VERSION 5.7 ;
  DIVIDERCHAR "/" ;
  BUSBITCHARS "[]" ;
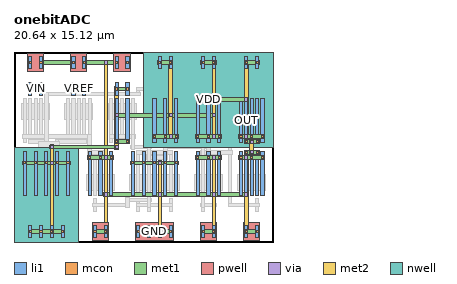
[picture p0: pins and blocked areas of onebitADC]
MACRO onebitADC
  CLASS BLOCK ;
  FOREIGN onebitADC ;
  ORIGIN 0.000 0.000 ;
  SIZE 20.640 BY 15.120 ;
  PIN VIN
    ANTENNAGATEAREA 0.630000 ;
    PORT
      LAYER li1 ;
        RECT 1.165 11.675 1.415 12.685 ;
        RECT 2.025 11.675 2.275 12.685 ;
      LAYER mcon ;
        RECT 1.205 12.095 1.375 12.265 ;
        RECT 2.065 12.095 2.235 12.265 ;
      LAYER met1 ;
        RECT 1.120 12.040 2.320 12.320 ;
    END
  END VIN
  PIN GND
    ANTENNADIFFAREA 7.036400 ;
    PORT
      LAYER pwell ;
        RECT 1.075 13.590 2.365 14.970 ;
        RECT 4.515 13.590 5.805 14.970 ;
        RECT 7.955 13.590 9.245 14.970 ;
        RECT 6.235 0.150 7.525 1.530 ;
        RECT 9.675 0.150 12.685 1.530 ;
        RECT 14.835 0.150 16.125 1.530 ;
        RECT 18.275 0.150 19.565 1.530 ;
      LAYER li1 ;
        RECT 1.165 13.775 1.415 14.785 ;
        RECT 2.025 13.775 2.275 14.785 ;
        RECT 4.605 13.775 4.855 14.785 ;
        RECT 5.465 13.775 5.715 14.785 ;
        RECT 8.045 13.775 8.295 14.785 ;
        RECT 8.905 13.775 9.155 14.785 ;
        RECT 5.895 3.695 6.145 7.225 ;
        RECT 6.755 3.695 7.005 7.225 ;
        RECT 7.615 3.695 7.865 7.225 ;
        RECT 9.335 3.695 9.585 7.225 ;
        RECT 10.195 3.695 10.445 7.225 ;
        RECT 11.055 3.695 11.305 7.225 ;
        RECT 11.915 3.695 12.165 7.225 ;
        RECT 12.775 3.695 13.025 7.225 ;
        RECT 14.495 3.695 14.745 7.225 ;
        RECT 15.355 3.695 15.605 7.225 ;
        RECT 16.215 3.695 16.465 7.225 ;
        RECT 17.935 3.695 18.185 7.225 ;
        RECT 18.795 3.695 19.045 7.225 ;
        RECT 19.655 3.695 19.905 7.225 ;
        RECT 6.325 0.335 6.575 1.345 ;
        RECT 7.185 0.335 7.435 1.345 ;
        RECT 9.765 0.335 10.015 1.345 ;
        RECT 10.625 0.335 10.875 1.345 ;
        RECT 11.485 0.335 11.735 1.345 ;
        RECT 12.345 0.335 12.595 1.345 ;
        RECT 14.925 0.335 15.175 1.345 ;
        RECT 15.785 0.335 16.035 1.345 ;
        RECT 18.365 0.335 18.615 1.345 ;
        RECT 19.225 0.335 19.475 1.345 ;
      LAYER mcon ;
        RECT 1.205 14.195 1.375 14.365 ;
        RECT 2.065 14.195 2.235 14.365 ;
        RECT 4.645 14.195 4.815 14.365 ;
        RECT 5.505 14.195 5.675 14.365 ;
        RECT 8.085 14.195 8.255 14.365 ;
        RECT 8.945 14.195 9.115 14.365 ;
        RECT 5.935 6.635 6.105 6.805 ;
        RECT 6.795 6.635 6.965 6.805 ;
        RECT 7.655 6.635 7.825 6.805 ;
        RECT 9.375 6.215 9.545 6.385 ;
        RECT 10.235 6.215 10.405 6.385 ;
        RECT 11.095 6.215 11.265 6.385 ;
        RECT 11.955 6.215 12.125 6.385 ;
        RECT 12.815 6.215 12.985 6.385 ;
        RECT 14.535 6.635 14.705 6.805 ;
        RECT 15.395 6.635 15.565 6.805 ;
        RECT 16.255 6.635 16.425 6.805 ;
        RECT 17.975 6.635 18.145 6.805 ;
        RECT 18.835 6.635 19.005 6.805 ;
        RECT 19.695 6.635 19.865 6.805 ;
        RECT 6.365 0.755 6.535 0.925 ;
        RECT 7.225 0.755 7.395 0.925 ;
        RECT 9.805 0.755 9.975 0.925 ;
        RECT 10.665 0.755 10.835 0.925 ;
        RECT 11.525 0.755 11.695 0.925 ;
        RECT 12.385 0.755 12.555 0.925 ;
        RECT 14.965 0.755 15.135 0.925 ;
        RECT 15.825 0.755 15.995 0.925 ;
        RECT 18.405 0.755 18.575 0.925 ;
        RECT 19.265 0.755 19.435 0.925 ;
      LAYER met1 ;
        RECT 1.120 14.140 9.200 14.420 ;
        RECT 5.850 6.580 7.910 6.860 ;
        RECT 14.450 6.580 16.510 6.860 ;
        RECT 17.890 6.580 19.950 6.860 ;
        RECT 9.290 6.160 13.070 6.440 ;
        RECT 7.150 3.640 18.650 3.920 ;
        RECT 6.280 0.700 7.480 0.980 ;
        RECT 9.720 0.700 12.640 0.980 ;
        RECT 14.880 0.700 16.080 0.980 ;
        RECT 18.320 0.700 19.520 0.980 ;
      LAYER via ;
        RECT 7.180 14.150 7.440 14.410 ;
        RECT 7.180 6.590 7.440 6.850 ;
        RECT 15.780 6.590 16.040 6.850 ;
        RECT 18.360 6.590 18.620 6.850 ;
        RECT 11.480 6.170 11.740 6.430 ;
        RECT 7.180 3.650 7.440 3.910 ;
        RECT 11.480 3.650 11.740 3.910 ;
        RECT 15.780 3.650 16.040 3.910 ;
        RECT 18.360 3.650 18.620 3.910 ;
        RECT 7.180 0.710 7.440 0.970 ;
        RECT 11.480 0.710 11.740 0.970 ;
        RECT 15.780 0.710 16.040 0.970 ;
        RECT 18.360 0.710 18.620 0.970 ;
      LAYER met2 ;
        RECT 7.170 0.680 7.450 14.440 ;
        RECT 11.470 0.680 11.750 6.460 ;
        RECT 15.770 0.680 16.050 6.880 ;
        RECT 18.350 0.680 18.630 6.880 ;
    END
  END GND
  PIN OUT
    ANTENNADIFFAREA 1.176000 ;
    PORT
      LAYER li1 ;
        RECT 18.365 7.895 18.615 11.425 ;
        RECT 19.225 7.895 19.475 11.425 ;
        RECT 18.365 3.695 18.615 7.225 ;
        RECT 19.225 3.695 19.475 7.225 ;
      LAYER mcon ;
        RECT 18.405 7.895 18.575 8.065 ;
        RECT 19.265 7.895 19.435 8.065 ;
        RECT 18.405 7.055 18.575 7.225 ;
        RECT 19.265 7.055 19.435 7.225 ;
      LAYER met1 ;
        RECT 18.320 7.840 19.520 8.120 ;
        RECT 18.320 7.000 19.520 7.280 ;
      LAYER via ;
        RECT 18.790 7.850 19.050 8.110 ;
        RECT 18.790 7.010 19.050 7.270 ;
      LAYER met2 ;
        RECT 18.780 6.980 19.060 8.140 ;
    END
  END OUT
  PIN VDD
    ANTENNAGATEAREA 0.630000 ;
    ANTENNADIFFAREA 6.482000 ;
    PORT
      LAYER nwell ;
        RECT 10.320 7.560 20.640 15.120 ;
        RECT 0.000 0.000 5.160 7.560 ;
      LAYER li1 ;
        RECT 11.485 13.775 11.735 14.785 ;
        RECT 12.345 13.775 12.595 14.785 ;
        RECT 14.925 13.775 15.175 14.785 ;
        RECT 15.785 13.775 16.035 14.785 ;
        RECT 18.365 13.775 18.615 14.785 ;
        RECT 19.225 13.775 19.475 14.785 ;
        RECT 8.045 11.675 8.295 12.685 ;
        RECT 8.905 11.675 9.155 12.685 ;
        RECT 8.045 7.895 8.295 11.425 ;
        RECT 8.905 7.895 9.155 11.425 ;
        RECT 11.055 7.895 11.305 11.425 ;
        RECT 11.915 7.895 12.165 11.425 ;
        RECT 12.775 7.895 13.025 11.425 ;
        RECT 14.495 7.895 14.745 11.425 ;
        RECT 15.355 7.895 15.605 11.425 ;
        RECT 16.215 7.895 16.465 11.425 ;
        RECT 17.935 7.895 18.185 11.425 ;
        RECT 18.795 7.895 19.045 11.425 ;
        RECT 19.655 7.895 19.905 11.425 ;
        RECT 0.735 3.695 0.985 7.225 ;
        RECT 1.595 3.695 1.845 7.225 ;
        RECT 2.455 3.695 2.705 7.225 ;
        RECT 3.315 3.695 3.565 7.225 ;
        RECT 4.175 3.695 4.425 7.225 ;
        RECT 1.165 0.335 1.415 1.345 ;
        RECT 2.025 0.335 2.275 1.345 ;
        RECT 2.885 0.335 3.135 1.345 ;
        RECT 3.745 0.335 3.995 1.345 ;
      LAYER mcon ;
        RECT 11.525 14.195 11.695 14.365 ;
        RECT 12.385 14.195 12.555 14.365 ;
        RECT 14.965 14.195 15.135 14.365 ;
        RECT 15.825 14.195 15.995 14.365 ;
        RECT 18.405 14.195 18.575 14.365 ;
        RECT 19.265 14.195 19.435 14.365 ;
        RECT 8.085 12.095 8.255 12.265 ;
        RECT 8.945 12.095 9.115 12.265 ;
        RECT 8.085 7.895 8.255 8.065 ;
        RECT 8.945 7.895 9.115 8.065 ;
        RECT 11.095 8.315 11.265 8.485 ;
        RECT 11.955 8.315 12.125 8.485 ;
        RECT 12.815 8.315 12.985 8.485 ;
        RECT 14.535 8.315 14.705 8.485 ;
        RECT 15.395 8.315 15.565 8.485 ;
        RECT 16.255 8.315 16.425 8.485 ;
        RECT 17.975 8.315 18.145 8.485 ;
        RECT 18.835 8.315 19.005 8.485 ;
        RECT 19.695 8.315 19.865 8.485 ;
        RECT 0.775 6.215 0.945 6.385 ;
        RECT 1.635 6.215 1.805 6.385 ;
        RECT 2.495 6.215 2.665 6.385 ;
        RECT 3.355 6.215 3.525 6.385 ;
        RECT 4.215 6.215 4.385 6.385 ;
        RECT 1.205 0.755 1.375 0.925 ;
        RECT 2.065 0.755 2.235 0.925 ;
        RECT 2.925 0.755 3.095 0.925 ;
        RECT 3.785 0.755 3.955 0.925 ;
      LAYER met1 ;
        RECT 11.440 14.140 12.640 14.420 ;
        RECT 14.880 14.140 16.080 14.420 ;
        RECT 18.320 14.140 19.520 14.420 ;
        RECT 8.000 12.040 9.200 12.320 ;
        RECT 15.750 11.200 18.650 11.480 ;
        RECT 8.010 9.940 16.070 10.220 ;
        RECT 11.010 8.260 13.070 8.540 ;
        RECT 14.450 8.260 16.510 8.540 ;
        RECT 17.890 8.260 19.950 8.540 ;
        RECT 8.000 7.840 9.200 8.120 ;
        RECT 2.850 7.420 8.330 7.700 ;
        RECT 0.690 6.160 4.470 6.440 ;
        RECT 1.120 0.700 4.040 0.980 ;
      LAYER via ;
        RECT 12.340 14.150 12.600 14.410 ;
        RECT 15.780 14.150 16.040 14.410 ;
        RECT 18.360 14.150 18.620 14.410 ;
        RECT 8.040 12.050 8.300 12.310 ;
        RECT 15.780 11.210 16.040 11.470 ;
        RECT 18.360 11.210 18.620 11.470 ;
        RECT 8.040 9.950 8.300 10.210 ;
        RECT 12.340 9.950 12.600 10.210 ;
        RECT 15.780 9.950 16.040 10.210 ;
        RECT 12.340 8.270 12.600 8.530 ;
        RECT 15.780 8.270 16.040 8.530 ;
        RECT 18.360 8.270 18.620 8.530 ;
        RECT 8.040 7.850 8.300 8.110 ;
        RECT 2.880 7.430 3.140 7.690 ;
        RECT 8.040 7.430 8.300 7.690 ;
        RECT 2.880 6.170 3.140 6.430 ;
        RECT 2.880 0.710 3.140 0.970 ;
      LAYER met2 ;
        RECT 2.870 0.680 3.150 7.720 ;
        RECT 8.030 7.400 8.310 12.340 ;
        RECT 12.330 8.240 12.610 14.440 ;
        RECT 15.770 8.240 16.050 14.440 ;
        RECT 18.350 8.240 18.630 14.440 ;
    END
  END VDD
  PIN VREF
    ANTENNAGATEAREA 0.630000 ;
    PORT
      LAYER li1 ;
        RECT 4.605 11.675 4.855 12.685 ;
        RECT 5.465 11.675 5.715 12.685 ;
      LAYER mcon ;
        RECT 4.645 12.095 4.815 12.265 ;
        RECT 5.505 12.095 5.675 12.265 ;
      LAYER met1 ;
        RECT 4.560 12.040 5.760 12.320 ;
    END
  END VREF
  OBS
      LAYER pwell ;
        RECT 0.605 9.740 2.835 11.050 ;
        RECT 4.045 9.740 6.275 11.050 ;
        RECT 7.485 9.740 9.715 11.050 ;
        RECT 5.765 4.070 7.995 5.380 ;
        RECT 9.205 4.070 13.155 5.380 ;
        RECT 14.365 4.070 16.595 5.380 ;
        RECT 17.805 4.070 20.035 5.380 ;
      LAYER li1 ;
        RECT 9.765 11.675 10.015 12.265 ;
        RECT 11.485 11.675 11.735 12.685 ;
        RECT 12.345 11.675 12.595 12.685 ;
        RECT 14.925 11.675 15.175 12.685 ;
        RECT 15.785 11.675 16.035 12.685 ;
        RECT 0.735 7.895 0.985 11.425 ;
        RECT 1.165 7.895 1.415 11.425 ;
        RECT 1.595 7.895 1.845 11.425 ;
        RECT 2.025 7.895 2.275 11.425 ;
        RECT 2.455 7.895 2.705 11.425 ;
        RECT 4.175 7.895 4.425 11.425 ;
        RECT 4.605 7.895 4.855 11.425 ;
        RECT 5.035 7.895 5.285 11.425 ;
        RECT 5.465 7.895 5.715 11.425 ;
        RECT 5.895 7.895 6.145 11.425 ;
        RECT 7.615 7.895 7.865 11.425 ;
        RECT 8.475 7.895 8.725 11.425 ;
        RECT 9.335 7.895 9.585 11.425 ;
        RECT 11.485 7.895 11.735 11.425 ;
        RECT 12.345 7.895 12.595 11.425 ;
        RECT 14.925 7.895 15.175 11.425 ;
        RECT 15.785 7.895 16.035 11.425 ;
        RECT 1.165 3.695 1.415 7.225 ;
        RECT 2.025 3.695 2.275 7.225 ;
        RECT 2.885 3.695 3.135 7.225 ;
        RECT 3.745 3.695 3.995 7.225 ;
        RECT 6.325 3.695 6.575 7.225 ;
        RECT 7.185 3.695 7.435 7.225 ;
        RECT 9.765 3.695 10.015 7.225 ;
        RECT 10.625 3.695 10.875 7.225 ;
        RECT 11.485 3.695 11.735 7.225 ;
        RECT 12.345 3.695 12.595 7.225 ;
        RECT 14.925 3.695 15.175 7.225 ;
        RECT 15.785 3.695 16.035 7.225 ;
        RECT 1.165 2.435 1.415 3.445 ;
        RECT 2.025 2.435 2.275 3.445 ;
        RECT 2.885 2.435 3.135 3.445 ;
        RECT 3.745 2.435 3.995 3.445 ;
        RECT 6.325 2.435 6.575 3.445 ;
        RECT 7.185 2.435 7.435 3.445 ;
        RECT 9.765 2.435 10.015 3.445 ;
        RECT 10.625 2.435 10.875 3.445 ;
        RECT 11.485 2.435 11.735 3.445 ;
        RECT 12.345 2.435 12.595 3.445 ;
        RECT 14.925 2.435 15.175 3.445 ;
        RECT 15.785 2.435 16.035 3.445 ;
        RECT 17.075 2.855 17.325 12.265 ;
        RECT 18.365 11.675 18.615 12.685 ;
        RECT 19.225 11.675 19.475 12.685 ;
        RECT 18.365 2.435 18.615 3.445 ;
        RECT 19.225 2.435 19.475 3.445 ;
      LAYER mcon ;
        RECT 9.805 12.095 9.975 12.265 ;
        RECT 9.805 11.675 9.975 11.845 ;
        RECT 11.525 12.095 11.695 12.265 ;
        RECT 12.385 12.095 12.555 12.265 ;
        RECT 14.965 12.095 15.135 12.265 ;
        RECT 15.825 12.095 15.995 12.265 ;
        RECT 17.115 12.095 17.285 12.265 ;
        RECT 0.775 8.315 0.945 8.485 ;
        RECT 1.205 7.895 1.375 8.065 ;
        RECT 1.635 8.315 1.805 8.485 ;
        RECT 2.065 7.895 2.235 8.065 ;
        RECT 2.495 8.315 2.665 8.485 ;
        RECT 4.215 8.315 4.385 8.485 ;
        RECT 4.645 7.895 4.815 8.065 ;
        RECT 5.075 8.315 5.245 8.485 ;
        RECT 5.505 7.895 5.675 8.065 ;
        RECT 5.935 8.315 6.105 8.485 ;
        RECT 7.655 8.315 7.825 8.485 ;
        RECT 8.515 8.315 8.685 8.485 ;
        RECT 9.375 8.315 9.545 8.485 ;
        RECT 11.525 7.895 11.695 8.065 ;
        RECT 12.385 7.895 12.555 8.065 ;
        RECT 14.965 7.895 15.135 8.065 ;
        RECT 15.825 7.895 15.995 8.065 ;
        RECT 18.405 12.095 18.575 12.265 ;
        RECT 19.265 12.095 19.435 12.265 ;
        RECT 1.205 7.055 1.375 7.225 ;
        RECT 2.065 6.635 2.235 6.805 ;
        RECT 2.925 6.635 3.095 6.805 ;
        RECT 3.785 7.055 3.955 7.225 ;
        RECT 6.365 7.055 6.535 7.225 ;
        RECT 7.225 7.055 7.395 7.225 ;
        RECT 9.805 7.055 9.975 7.225 ;
        RECT 10.665 6.635 10.835 6.805 ;
        RECT 11.525 6.635 11.695 6.805 ;
        RECT 12.385 7.055 12.555 7.225 ;
        RECT 14.965 7.055 15.135 7.225 ;
        RECT 15.825 7.055 15.995 7.225 ;
        RECT 17.115 7.055 17.285 7.225 ;
        RECT 1.205 2.855 1.375 3.025 ;
        RECT 2.065 2.855 2.235 3.025 ;
        RECT 2.925 2.855 3.095 3.025 ;
        RECT 3.785 2.855 3.955 3.025 ;
        RECT 6.365 2.855 6.535 3.025 ;
        RECT 7.225 2.855 7.395 3.025 ;
        RECT 9.805 2.855 9.975 3.025 ;
        RECT 10.665 2.855 10.835 3.025 ;
        RECT 11.525 2.855 11.695 3.025 ;
        RECT 12.385 2.855 12.555 3.025 ;
        RECT 14.965 2.855 15.135 3.025 ;
        RECT 15.825 2.855 15.995 3.025 ;
        RECT 17.115 2.855 17.285 3.025 ;
        RECT 18.405 2.855 18.575 3.025 ;
        RECT 19.265 2.855 19.435 3.025 ;
      LAYER met1 ;
        RECT 9.720 12.040 12.640 12.320 ;
        RECT 14.880 12.040 16.080 12.320 ;
        RECT 17.030 12.040 19.520 12.320 ;
        RECT 2.420 11.620 10.060 11.900 ;
        RECT 0.690 8.260 6.190 8.540 ;
        RECT 7.570 8.260 9.630 8.540 ;
        RECT 1.120 7.840 2.740 8.120 ;
        RECT 3.280 7.840 5.760 8.120 ;
        RECT 11.440 7.840 12.640 8.120 ;
        RECT 14.880 7.840 16.080 8.120 ;
        RECT 9.300 7.420 10.910 7.700 ;
        RECT 11.880 7.420 15.210 7.700 ;
        RECT 1.120 7.000 4.040 7.280 ;
        RECT 5.860 7.000 7.480 7.280 ;
        RECT 9.720 7.000 12.640 7.280 ;
        RECT 14.880 7.000 17.370 7.280 ;
        RECT 1.980 6.580 3.180 6.860 ;
        RECT 10.580 6.580 12.200 6.860 ;
        RECT 8.870 3.220 10.910 3.500 ;
        RECT 1.120 2.800 4.040 3.080 ;
        RECT 6.280 2.800 9.190 3.080 ;
        RECT 9.720 2.800 12.640 3.080 ;
        RECT 14.880 2.800 16.080 3.080 ;
        RECT 17.030 2.800 19.520 3.080 ;
      LAYER via ;
        RECT 14.920 12.050 15.180 12.310 ;
        RECT 2.450 11.630 2.710 11.890 ;
        RECT 5.890 8.270 6.150 8.530 ;
        RECT 9.330 8.270 9.590 8.530 ;
        RECT 2.450 7.850 2.710 8.110 ;
        RECT 3.310 7.850 3.570 8.110 ;
        RECT 11.910 7.850 12.170 8.110 ;
        RECT 15.350 7.850 15.610 8.110 ;
        RECT 9.330 7.430 9.590 7.690 ;
        RECT 10.620 7.430 10.880 7.690 ;
        RECT 11.910 7.430 12.170 7.690 ;
        RECT 14.920 7.430 15.180 7.690 ;
        RECT 2.020 7.010 2.280 7.270 ;
        RECT 5.890 7.010 6.150 7.270 ;
        RECT 10.620 7.010 10.880 7.270 ;
        RECT 15.350 7.010 15.610 7.270 ;
        RECT 2.450 6.590 2.710 6.850 ;
        RECT 11.910 6.590 12.170 6.850 ;
        RECT 8.900 3.230 9.160 3.490 ;
        RECT 10.620 3.230 10.880 3.490 ;
        RECT 2.020 2.810 2.280 3.070 ;
        RECT 8.900 2.810 9.160 3.070 ;
        RECT 10.620 2.810 10.880 3.070 ;
        RECT 14.920 2.810 15.180 3.070 ;
      LAYER met2 ;
        RECT 2.010 2.780 2.290 7.745 ;
        RECT 2.440 6.560 2.720 11.920 ;
        RECT 3.300 7.375 3.580 8.140 ;
        RECT 5.880 6.980 6.160 8.560 ;
        RECT 9.320 7.400 9.600 8.560 ;
        RECT 8.890 2.780 9.170 3.520 ;
        RECT 10.610 2.780 10.890 7.720 ;
        RECT 11.900 6.560 12.180 8.140 ;
        RECT 14.910 2.780 15.190 12.340 ;
        RECT 15.340 6.980 15.620 8.140 ;
      LAYER via2 ;
        RECT 2.010 7.420 2.290 7.700 ;
        RECT 3.300 7.420 3.580 7.700 ;
      LAYER met3 ;
        RECT 1.985 7.160 3.605 7.960 ;
  END
END onebitADC
END LIBRARY

